VERSION 5.7 ;
  NOWIREEXTENSIONATPIN ON ;
  DIVIDERCHAR "/" ;
  BUSBITCHARS "[]" ;
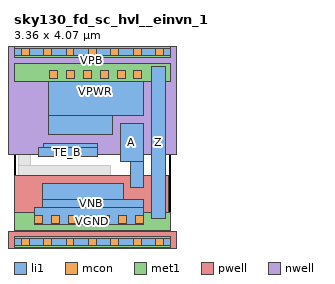
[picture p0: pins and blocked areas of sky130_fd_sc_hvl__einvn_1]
MACRO sky130_fd_sc_hvl__einvn_1
  CLASS BLOCK ;
  FOREIGN sky130_fd_sc_hvl__einvn_1 ;
  ORIGIN 0.000 0.000 ;
  SIZE 3.360 BY 4.070 ;
  PIN A
    ANTENNAGATEAREA 1.125000 ;
    PORT
      LAYER li1 ;
        RECT 2.275 1.725 2.780 2.540 ;
        RECT 2.505 1.160 2.780 1.725 ;
    END
  END A
  PIN TE_B
    ANTENNAGATEAREA 1.335000 ;
    PORT
      LAYER li1 ;
        RECT 0.635 2.025 1.795 2.120 ;
        RECT 0.515 1.825 1.795 2.025 ;
    END
  END TE_B
  PIN VGND
    USE GROUND ;
    PORT
      LAYER li1 ;
        RECT 0.610 0.900 2.335 1.245 ;
        RECT 0.610 0.740 2.770 0.900 ;
        RECT 0.440 0.365 2.770 0.740 ;
      LAYER mcon ;
        RECT 0.440 0.395 0.610 0.565 ;
        RECT 0.800 0.395 0.970 0.565 ;
        RECT 1.160 0.395 1.330 0.565 ;
        RECT 1.520 0.395 1.690 0.565 ;
        RECT 1.880 0.395 2.050 0.565 ;
        RECT 2.240 0.395 2.410 0.565 ;
        RECT 2.600 0.395 2.770 0.565 ;
      LAYER met1 ;
        RECT 0.000 0.255 3.360 0.625 ;
    END
  END VGND
  PIN VNB
    ANTENNADIFFAREA 0.571200 ;
    PORT
      LAYER pwell ;
        RECT 0.020 0.215 3.310 1.415 ;
        RECT -0.130 -0.215 3.490 0.215 ;
      LAYER li1 ;
        RECT 0.000 -0.085 3.360 0.085 ;
      LAYER mcon ;
        RECT 0.155 -0.085 0.325 0.085 ;
        RECT 0.635 -0.085 0.805 0.085 ;
        RECT 1.115 -0.085 1.285 0.085 ;
        RECT 1.595 -0.085 1.765 0.085 ;
        RECT 2.075 -0.085 2.245 0.085 ;
        RECT 2.555 -0.085 2.725 0.085 ;
        RECT 3.035 -0.085 3.205 0.085 ;
      LAYER met1 ;
        RECT 0.000 -0.115 3.360 0.115 ;
    END
  END VNB
  PIN VPB
    ANTENNADIFFAREA 0.571200 ;
    PORT
      LAYER nwell ;
        RECT -0.330 1.885 3.690 4.485 ;
      LAYER li1 ;
        RECT 0.000 3.985 3.360 4.155 ;
      LAYER mcon ;
        RECT 0.155 3.985 0.325 4.155 ;
        RECT 0.635 3.985 0.805 4.155 ;
        RECT 1.115 3.985 1.285 4.155 ;
        RECT 1.595 3.985 1.765 4.155 ;
        RECT 2.075 3.985 2.245 4.155 ;
        RECT 2.555 3.985 2.725 4.155 ;
        RECT 3.035 3.985 3.205 4.155 ;
      LAYER met1 ;
        RECT 0.000 3.955 3.360 4.185 ;
    END
  END VPB
  PIN VPWR
    USE POWER ;
    PORT
      LAYER li1 ;
        RECT 0.740 2.710 2.770 3.755 ;
        RECT 0.740 2.300 2.105 2.710 ;
      LAYER mcon ;
        RECT 0.770 3.505 0.940 3.675 ;
        RECT 1.130 3.505 1.300 3.675 ;
        RECT 1.490 3.505 1.660 3.675 ;
        RECT 1.850 3.505 2.020 3.675 ;
        RECT 2.210 3.505 2.380 3.675 ;
        RECT 2.570 3.505 2.740 3.675 ;
      LAYER met1 ;
        RECT 0.000 3.445 3.360 3.815 ;
    END
  END VPWR
  PIN Z
    ANTENNADIFFAREA 0.641250 ;
    PORT
      LAYER li1 ;
        RECT 2.950 0.495 3.235 3.755 ;
    END
  END Z
  OBS
      LAYER li1 ;
        RECT 0.090 2.300 0.535 3.025 ;
        RECT 0.090 2.195 0.455 2.300 ;
        RECT 0.090 1.645 0.345 2.195 ;
        RECT 0.090 1.425 2.065 1.645 ;
        RECT 0.090 0.910 0.440 1.425 ;
  END
END sky130_fd_sc_hvl__einvn_1
END LIBRARY

